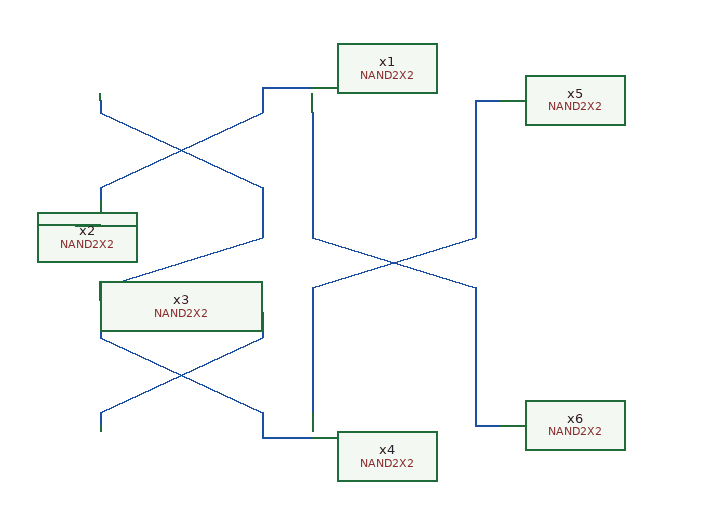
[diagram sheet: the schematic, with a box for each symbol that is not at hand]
v {xschem version=3.0.0 file_version=1.2 }
G {}
K {}
V {}
S {}
E {}
N -20 120 -20 140 {
lab=#net1}
N -20 40 -20 60 {
lab=#net2}
N -20 140 20 140 {
lab=#net1}
N -20 -140 -20 -120 {
lab=#net3}
N -20 -60 -20 -40 {
lab=#net4}
N -150 -60 -150 -50 {
lab=#net3}
N -150 -60 -20 -120 {
lab=#net3}
N -150 -130 -150 -120 {
lab=#net4}
N -150 -120 -20 -60 {
lab=#net4}
N -150 120 -150 130 {
lab=#net2}
N -150 120 -20 60 {
lab=#net2}
N -150 50 -150 60 {
lab=#net1}
N -150 60 -20 120 {
lab=#net1}
N -20 -140 20 -140 {}
N 150 20 150 130 {}
N 20 -20 150 20 {}
N 20 -120 20 -20 {}
N 20 20 20 120 {}
N 20 20 150 -20 {}
N 150 -130 150 -20 {}
N 150 130 170 130 {}
N 150 -130 170 -130 {}
N -150 20 -150 30 {}
N -150 20 -20 -20 {}
N -20 -40 -20 -20 {}
N -170 -30 -150 -30 {}
C {NAND2X2.sym} -20 -140 0 0 {name=x1}
C {NAND2X2.sym} -20 -40 0 0 {name=x2}
C {NAND2X2.sym} -20 40 0 0 {name=x3}
C {NAND2X2.sym} -20 140 0 0 {name=x4}
C {NAND2X2.sym} 150 -130 0 0 {name=x5}
C {NAND2X2.sym} 150 130 0 0 {name=x6}
